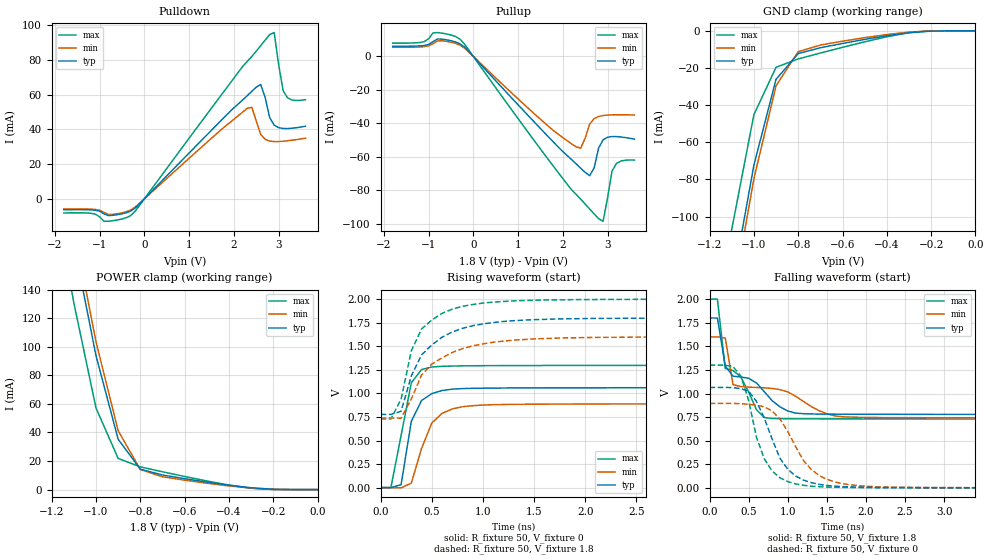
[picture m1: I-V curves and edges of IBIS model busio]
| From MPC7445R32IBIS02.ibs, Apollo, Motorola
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| *   busio Model   *
[Model]   busio
Model_type   I/O
Polarity   Non-Inverting
Vinl = 0.63V
Vinh = 1.17V
Vmeas = 0.9V
Cref = 0
Rref = 50
Vref = 0.9V
|   typ   min   max
C_comp   3.734270e-12   3.191948e-12   3.962333e-12
|   typ   min   max
[Voltage range]   1.8V   1.6V   2.0V
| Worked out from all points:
|   slope of the pulldown table from 0 to 0.27 V, typ, clamps not added: 37.8 ohm
|   slope of the pullup table from 0 to 0.27 V, typ, clamps not added: 34.3 ohm
|   GND clamp passes 1 mA (typ) near -0.30 V on its own axis
|   POWER clamp passes 1 mA (typ) near -0.27 V on its own axis
|   falling waveform, R_fixture 50, V_fixture 1.8: 20-80 % time 600ps typ, 976ps min, 382ps max; typ from 1.8 V to 0.777 V
|   rising waveform, R_fixture 50, V_fixture 0: 20-80 % time 140ps typ, 194ps min, 140ps max; typ from 0 V to 1.06 V
|   falling waveform, R_fixture 50, V_fixture 0: 20-80 % time 350ps typ, 415ps min, 281ps max; typ from 1.06 V to 0 V
|   rising waveform, R_fixture 50, V_fixture 1.8: 20-80 % time 353ps typ, 403ps min, 257ps max; typ from 0.777 V to 1.8 V
[Pulldown]
|   Voltage   I(typ)   I(min)   I(max)
-1.8V     -6.256mA   -5.824mA   -8.112mA
-1.1V     -6.522mA   -6.074mA   -8.703mA
-900mV    -8.636mA   -7.785mA   -12.9mA
-300mV    -6.921mA   -6.362mA   -9.494mA
2.3V      59.38mA    52.07mA    79.09mA
2.4V      61.84mA    52.66mA    81.89mA
2.6V      65.75mA    37.05mA    88.12mA
2.8V      46.73mA    33.25mA    94.48mA
2.9V      42.43mA    32.96mA    95.65mA
3.1V      40.49mA    33.15mA    62.26mA
3.3V      40.64mA    33.74mA    56.87mA
3.6V      41.76mA    34.89mA    57.04mA
[GND_clamp]
-1.8V     -698.8mA   -707.6mA   -679.3mA
-1.1V     -138.6mA   -146.9mA   -106.9mA
-1V       -72.27mA   -79.58mA   -45.14mA
-900mV    -26.09mA   -29.56mA   -19.61mA
-800mV    -12.24mA   -11.22mA   -15.14mA
-700mV    -9.12mA    -7.662mA   -11.96mA
-500mV    -4.63mA    -3.688mA   -5.929mA
-300mV    -1.025mA   -694uA     -1.003mA
-200mV    -152.2uA   0A         0A
0V        0A         0A         0A
[Pullup]
-1.8V     6.064mA    5.429mA    7.901mA
-1.1V     6.471mA    5.79mA     8.75mA
-800mV    10.38mA    9.208mA    14.19mA
-300mV    7.492mA    6.715mA    10.32mA
2.3V      -64.17mA   -53.98mA   -82.41mA
2.4V      -66.7mA    -54.74mA   -85.15mA
2.6V      -71.17mA   -40.45mA   -91.06mA
2.7V      -66.53mA   -37.17mA   -93.97mA
2.9V      -49.8mA    -35.3mA    -98.37mA
3.1V      -47.82mA   -34.89mA   -68.36mA
3.3V      -48.1mA    -34.83mA   -62.4mA
3.6V      -49.35mA   -34.96mA   -61.87mA
[POWER_clamp]
-1.8V     819.2mA    829.9mA    787.7mA
-1.2V     258.3mA    269.3mA    217.2mA
-1.1V     172.1mA    182.9mA    130.7mA
-1V       93.78mA    103.6mA    57.14mA
-900mV    35.28mA    41.22mA    21.82mA
-800mV    14.31mA    14.12mA    15.94mA
-700mV    10.23mA    9.005mA    12.48mA
-500mV    5.248mA    4.498mA    6.042mA
-300mV    1.272mA    1.057mA    954.3uA
-200mV    243.4uA    204.7uA    0A
0V        0A         0A         0A
|   typ   min   max
[Ramp]
dV/dt_r   0.63798/1.18285e-10   0.53668/1.79334e-10   0.78033/9.86526e-11
dV/dt_f   0.61400/5.60663e-10   0.51660/9.84285e-10   0.76276/3.72264e-10
[Falling Waveform]
R_fixture = 50
V_fixture = 1.8
V_fixture_min = 1.6
V_fixture_max = 2.0
| time   V(typ)   V(min)   V(max)
0s        1.8V       1.6V       2V
100ps     1.8V       1.6V       2V
200ps     1.292V     1.588V     1.266V
300ps     1.183V     1.094V     1.243V
600ps     1.112V     1.064V     828.2mV
800ps     924.3mV    1.054V     735.9mV
1.1ns     792.4mV    971mV      732.2mV
1.5ns     781.4mV    784.8mV    731.4mV
1.9ns     780.2mV    748mV      731.1mV
19.7ns    776.6mV    738.9mV    728.7mV
[Rising Waveform]
R_fixture = 50
V_fixture = 0
V_fixture_min = 0
V_fixture_max = 0
| time   V(typ)   V(min)   V(max)
0s        454.6uV    417.2uV    392.7uV
100ps     465.4uV    414.4uV    -870.8uV
200ps     30.95mV    -2.469mV   553.3mV
300ps     703.3mV    47.84mV    1.112V
400ps     924.3mV    415mV      1.253V
500ps     997.2mV    685.1mV    1.28V
600ps     1.03V      788.2mV    1.287V
900ps     1.054V     869mV      1.293V
1.6ns     1.059V     885.6mV    1.296V
19.7ns    1.064V     894.9mV    1.301V
[Falling Waveform]
R_fixture = 50
V_fixture = 0
V_fixture_min = 0
V_fixture_max = 0
| time   V(typ)   V(min)   V(max)
0s        1.064V     894.9mV    1.301V
300ps     1.062V     895.2mV    1.285V
400ps     1.052V     892mV      1.185V
600ps     917.1mV    876.2mV    536.7mV
800ps     517.2mV    815.3mV    178.9mV
1ns       197.5mV    598mV      66.87mV
1.3ns     55.42mV    195.6mV    17.93mV
1.7ns     13.48mV    44.9mV     5.122mV
2.5ns     2.541mV    5.364mV    2.221mV
19.7ns    453.3uV    411.3uV    403.9uV
[Rising Waveform]
R_fixture = 50
V_fixture = 1.8
V_fixture_min = 1.6
V_fixture_max = 2.0
| time   V(typ)   V(min)   V(max)
0s        776.6mV    738.9mV    728.7mV
100ps     776.5mV    738.8mV    728.6mV
200ps     810.2mV    736.8mV    938.3mV
300ps     1.185V     940.4mV    1.451V
400ps     1.408V     1.195V     1.683V
500ps     1.513V     1.31V      1.778V
700ps     1.651V     1.434V     1.894V
1.2ns     1.763V     1.554V     1.975V
3.1ns     1.798V     1.599V     1.998V
19.7ns    1.799V     1.6V       2V
